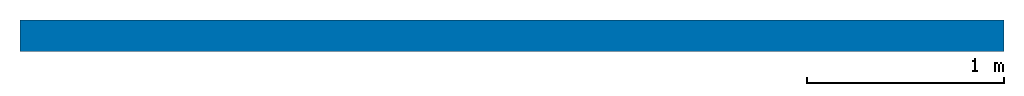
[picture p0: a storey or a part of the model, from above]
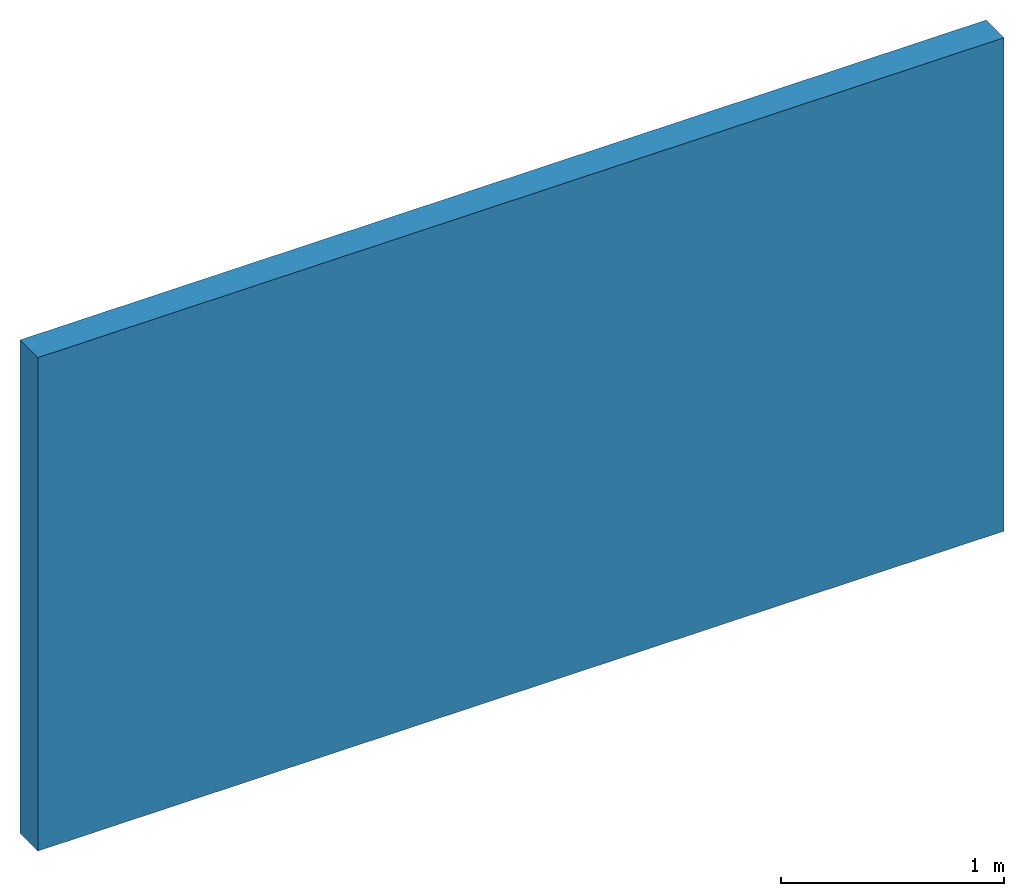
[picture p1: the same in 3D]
Properties of the parts of a building model (IFC2X3)

# File
Description: ViewDefinition [CoordinationView_V2.0]
File name: Wall_CLT60_Sughero
Time: 2021-04-27T17:54:19
Author: CadLine Ltd.
Organization: CadLine Ltd.
Written by: IfcOpenShell 0.5.0-dev
Made in: IFC file generated by ARCHline.XP 2021

# IfcProject, Project name
Description: Project number

# IfcSite, Site
LongName: Site; RefLatitude: 39, 13, 49; RefLongitude: 9, 7, 9; RefElevation: 0 m

# IfcBuilding, Architettura
LongName: Architettura; ElevationOfRefHeight: 0 m

# IfcBuildingStorey (4)
In: Architettura
Name | LongName | Elevation (m)
Fondazioni | Fondazioni | -3
Piano Terra | Piano Terra | 0
Piano Primo | Piano Primo | 3
Piano Secondo | Piano Secondo | 6

# IfcWallStandardCase: Università\PLES\Wall_CLT60_Sughero, Wall 1
In: Piano Terra
Type - Pset_WallCommon - Combustible: no; IsExternal: yes; ExtendToStructure: yes; Compartmentation: no
Material: Pannelli di sughero espanso con leganti (130 kg/m³) 0.1 m, X-lam Wall 0.06 m
Pset_WallCommon - ThermalTransmittance: 0.367232; LoadBearing: no
BaseQuantities - NominalLength: 5 m; NominalWidth: 0.16 m; NominalHeight: 2.7 m; GrossFootprintArea: 0.8 m2; NetFootprintArea: 0.8 m2; GrossSideArea: 13.5 m2; NetSideArea: 13.5 m2; NetSideAreaLeft: 13.5 m2; NetSideAreaRight: 13.5 m2; GrossSideAreaLeft: 13.5 m2; GrossSideAreaRight: 13.5 m2; GrossVolume: 2.16 m3; NetVolume: 2.16 m3
